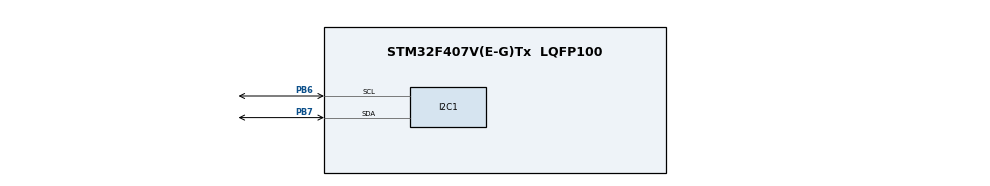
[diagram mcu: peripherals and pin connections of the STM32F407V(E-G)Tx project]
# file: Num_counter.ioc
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Mcu.Family=STM32F4
Mcu.Name=STM32F407V(E-G)Tx
Mcu.Package=LQFP100
NVIC.PriorityGroup=NVIC_PRIORITYGROUP_0
PB6.Mode=I2C
PB6.Signal=I2C1_SCL
PB7.Mode=I2C
PB7.Signal=I2C1_SDA
ProjectManager.HeapSize=0x200
ProjectManager.StackSize=0x400
ProjectManager.TargetToolchain=STM32CubeIDE
RCC.48MHZClocksFreq_Value=14285714.285714285
RCC.AHBFreq_Value=50000000
RCC.APB1CLKDivider=RCC_HCLK_DIV4
RCC.APB1Freq_Value=12500000
RCC.APB1TimFreq_Value=25000000
RCC.APB2CLKDivider=RCC_HCLK_DIV4
RCC.APB2Freq_Value=12500000
RCC.APB2TimFreq_Value=25000000
RCC.CortexFreq_Value=50000000
RCC.HCLKFreq_Value=50000000
RCC.HSE_VALUE=8000000
RCC.HSI_VALUE=16000000
RCC.LSE_VALUE=32768
RCC.PLLM=8
RCC.PLLN=50
RCC.PLLQ=7
RCC.SYSCLKFreq_VALUE=50000000
RCC.SYSCLKSource=RCC_SYSCLKSOURCE_PLLCLK
RCC.VCOOutputFreq_Value=100000000
board=STM32F407G-DISC1

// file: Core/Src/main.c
/* USER CODE BEGIN Header */
/**
  ******************************************************************************
  * @file           : main.c
  * @brief          : Main program body
  ******************************************************************************
  * @attention
  *
  * Copyright (c) 2025 STMicroelectronics.
  * All rights reserved.
  *
  * This software is licensed under terms that can be found in the LICENSE file
  * in the root directory of this software component.
  * If no LICENSE file comes with this software, it is provided AS-IS.
  *
  ******************************************************************************
  */
/* USER CODE END Header */
#include "main.h"
#include"lcd.h"

I2C_HandleTypeDef hi2c1;

void SystemClock_Config(void);
static void MX_GPIO_Init(void);
static void MX_I2C1_Init(void);

int main(void)
{

  /* USER CODE BEGIN 1 */
	uint8_t i;

  /* USER CODE END 1 */

  /* MCU Configuration--------------------------------------------------------*/

  /* Reset of all peripherals, Initializes the Flash interface and the Systick. */
  HAL_Init();

  /* Configure the system clock */
  SystemClock_Config();

  /* Initialize all configured peripherals */
  MX_GPIO_Init();
  MX_I2C1_Init();
  /* USER CODE BEGIN 2 */
  if(!lcd16x2_i2c_init(&hi2c1))
    {
  	  while(1);
    }

    lcd16x2_i2c_clear();

 //   lcd16x2_i2c_setCursor(0, 4);
 //   lcd16x2_i2c_printf("HELLO");

  /* USER CODE END 2 */

  /* Infinite loop */
  while (1)
  {

    /* USER CODE BEGIN 3 */
	  for(i=1;i<=20;i++)
	  {
		  HAL_GPIO_TogglePin(GPIOD, GPIO_PIN_12);
		  lcd16x2_i2c_setCursor(1, 0);
		  lcd16x2_i2c_printnum(i);
		  HAL_Delay(500);
	  }
	  lcd16x2_i2c_clear();
  }
  /* USER CODE END 3 */
}

void SystemClock_Config(void)
{
  RCC_OscInitTypeDef RCC_OscInitStruct = {0};
  RCC_ClkInitTypeDef RCC_ClkInitStruct = {0};

  /** Configure the main internal regulator output voltage
  */
  __HAL_RCC_PWR_CLK_ENABLE();
  __HAL_PWR_VOLTAGESCALING_CONFIG(PWR_REGULATOR_VOLTAGE_SCALE1);

  /** Initializes the RCC Oscillators according to the specified parameters
  * in the RCC_OscInitTypeDef structure.
  */
  RCC_OscInitStruct.OscillatorType = RCC_OSCILLATORTYPE_HSI;
  RCC_OscInitStruct.HSIState = RCC_HSI_ON;
  RCC_OscInitStruct.HSICalibrationValue = RCC_HSICALIBRATION_DEFAULT;
  RCC_OscInitStruct.PLL.PLLState = RCC_PLL_ON;
  RCC_OscInitStruct.PLL.PLLSource = RCC_PLLSOURCE_HSI;
  RCC_OscInitStruct.PLL.PLLM = 8;
  RCC_OscInitStruct.PLL.PLLN = 50;
  RCC_OscInitStruct.PLL.PLLP = RCC_PLLP_DIV4;
  RCC_OscInitStruct.PLL.PLLQ = 7;
  if (HAL_RCC_OscConfig(&RCC_OscInitStruct) != HAL_OK)
  {
    Error_Handler();
  }

  /** Initializes the CPU, AHB and APB buses clocks
  */
  RCC_ClkInitStruct.ClockType = RCC_CLOCKTYPE_HCLK|RCC_CLOCKTYPE_SYSCLK
                              |RCC_CLOCKTYPE_PCLK1|RCC_CLOCKTYPE_PCLK2;
  RCC_ClkInitStruct.SYSCLKSource = RCC_SYSCLKSOURCE_PLLCLK;
  RCC_ClkInitStruct.AHBCLKDivider = RCC_SYSCLK_DIV1;
  RCC_ClkInitStruct.APB1CLKDivider = RCC_HCLK_DIV4;
  RCC_ClkInitStruct.APB2CLKDivider = RCC_HCLK_DIV2;

  if (HAL_RCC_ClockConfig(&RCC_ClkInitStruct, FLASH_LATENCY_0) != HAL_OK)
  {
    Error_Handler();
  }
}

static void MX_I2C1_Init(void)
{

  hi2c1.Instance = I2C1;
  hi2c1.Init.ClockSpeed = 100000;
  hi2c1.Init.DutyCycle = I2C_DUTYCYCLE_2;
  hi2c1.Init.OwnAddress1 = 0;
  hi2c1.Init.AddressingMode = I2C_ADDRESSINGMODE_7BIT;
  hi2c1.Init.DualAddressMode = I2C_DUALADDRESS_DISABLE;
  hi2c1.Init.OwnAddress2 = 0;
  hi2c1.Init.GeneralCallMode = I2C_GENERALCALL_DISABLE;
  hi2c1.Init.NoStretchMode = I2C_NOSTRETCH_DISABLE;
  if (HAL_I2C_Init(&hi2c1) != HAL_OK)
  {
    Error_Handler();
  }

}

static void MX_GPIO_Init(void)
{
  GPIO_InitTypeDef GPIO_InitStruct = {0};

  /* GPIO Ports Clock Enable */
  __HAL_RCC_GPIOD_CLK_ENABLE();
  __HAL_RCC_GPIOB_CLK_ENABLE();

  /*Configure GPIO pin Output Level */
  HAL_GPIO_WritePin(GPIOD, GPIO_PIN_12, GPIO_PIN_RESET);

  /*Configure GPIO pin : PD12 */
  GPIO_InitStruct.Pin = GPIO_PIN_12;
  GPIO_InitStruct.Mode = GPIO_MODE_OUTPUT_PP;
  GPIO_InitStruct.Pull = GPIO_NOPULL;
  GPIO_InitStruct.Speed = GPIO_SPEED_FREQ_LOW;
  HAL_GPIO_Init(GPIOD, &GPIO_InitStruct);

}

void Error_Handler(void)
{
  __disable_irq();
  while (1)
  {
  }
}
